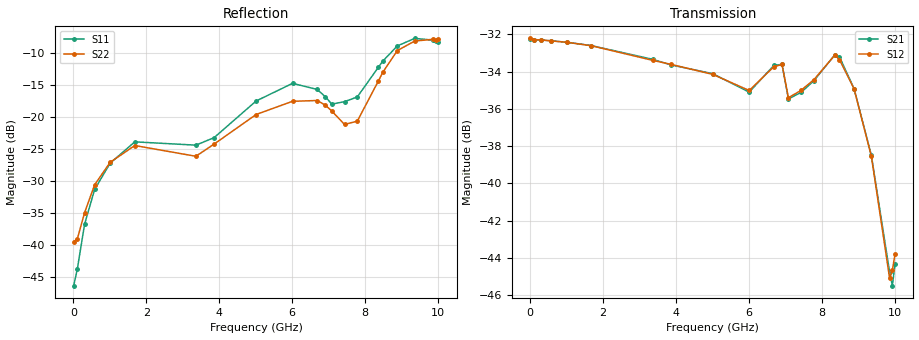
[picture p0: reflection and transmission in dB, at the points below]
! Device ID: PE43705
! Serial: 1
! Insertion: A
! Impedance: 50 ohm
! Temp: 25C
! VDD: 3.400V
! Attenuation Step: 31.25dB
#  Hz  S  RI  R  50
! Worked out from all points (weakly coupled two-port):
!   401 points, 10 MHz to 10.01 GHz, reference 50 ohm
!   highest |S21| = -32.24 dB at 10 MHz (marker M1); lowest = -45.5 dB at 9.935 GHz (marker M2)
!   lowest |S11| = -46.3 dB at 10 MHz (marker M3), VSWR 1.01, Z = 49.5 + j0.0446 ohm
!   |S11| at or under -10 dB: start of sweep to 8.673 GHz
!   |S22| runs from -39.6 to -7.8 dB; largest |S21 - S12| = 0.00072
!   S11 on the Smith chart (normalised r, x): 10 MHz: 0.99, +0.00; 7.435 GHz: 0.82, +0.16; 8.485 GHz: 0.84, +0.49; 9.36 GHz: 0.55, +0.49; 10.01 GHz: 0.49, +0.27
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1e7  -0.0048 0.000451  0.0244 -0.000105  0.0245 -0.000104  -0.0106 0.000569
1.1e8  -0.00449 0.00471  0.0243 -0.000641  0.0243 -0.000655  -0.00989 0.00519
3.1e8  -0.00682 0.0129  0.0242 -0.00174  0.0242 -0.00176  -0.0116 0.0137
5.85e8  -0.0148 0.0228  0.0239 -0.00326  0.0239 -0.00323  -0.0179 0.0235
1.01e9  -0.0337 0.0276  0.0233 -0.00543  0.0233 -0.00538  -0.0335 0.0289
1.685e9  -0.0614 0.0177  0.0218 -0.00858  0.0218 -0.00852  -0.0553 0.0228
3.36e9  -0.06 0.00504  0.016 -0.0144  0.016 -0.0142  -0.0467 0.0158
3.86e9  -0.063 0.0279  0.0143 -0.0151  0.0143 -0.0152  -0.0543 0.0286
5.01e9  -0.0992 0.0886  0.0112 -0.0162  0.0112 -0.0161  -0.0865 0.0584
6.01e9  -0.151 0.1029  0.00768 -0.0158  0.00789 -0.0159  -0.1156 0.0645
6.685e9  -0.1413 0.0828  0.007 -0.0195  0.00708 -0.0193  -0.1237 0.0523
6.91e9  -0.123 0.0745  0.00388 -0.0205  0.0038 -0.0205  -0.1134 0.049
7.085e9  -0.1078 0.065  0.00223 -0.0167  0.00241 -0.0168  -0.0982 0.0522
7.435e9  -0.0889 0.0969  0.00393 -0.0171  0.00408 -0.0173  -0.066 0.0573
7.785e9  -0.0429 0.1365  0.00415 -0.0184  0.00424 -0.0185  -0.0428 0.0821
8.36e9  -0.00851 0.243  -0.00324 -0.0219  -0.003 -0.0219  -0.0362 0.1863
8.485e9  -0.0148 0.2723  -0.00534 -0.0212  -0.00539 -0.0208  -0.0453 0.2186
8.885e9  -0.0679 0.3516  -0.00923 -0.0154  -0.00919 -0.0154  -0.1081 0.3114
9.36e9  -0.1709 0.3728  -0.00811 -0.00868  -0.00778 -0.00889  -0.2138 0.3269
9.86e9  -0.2783 0.2834  -0.00211 -0.00537  -0.00204 -0.00517  -0.3363 0.2224
9.935e9  -0.2943 0.2603  -0.00107 -0.0052  -0.000827 -0.00578  -0.3527 0.1914
1.001e10  -0.3022 0.2362  0.000438 -0.00607  0.000316 -0.00646  -0.3673 0.1633
